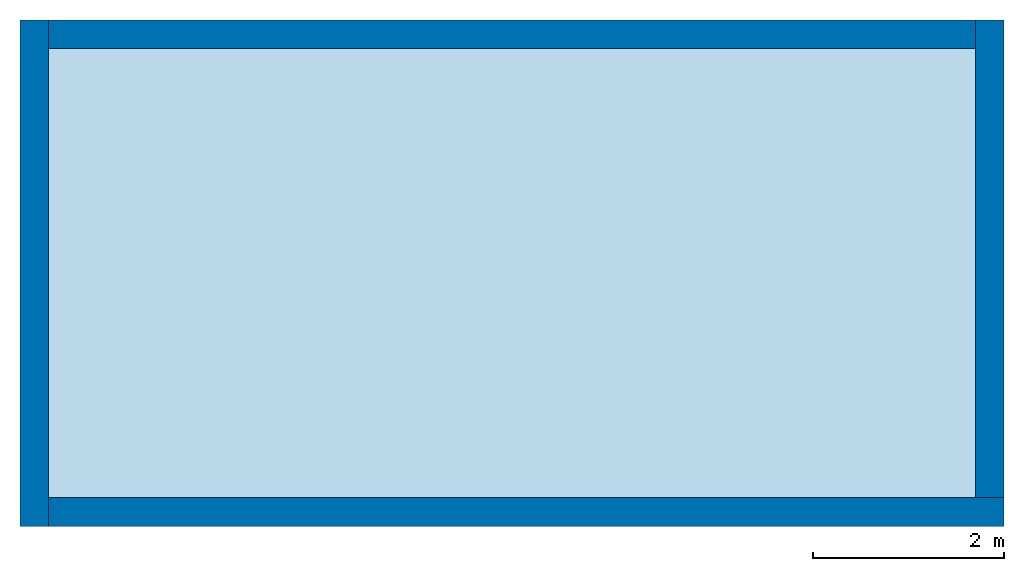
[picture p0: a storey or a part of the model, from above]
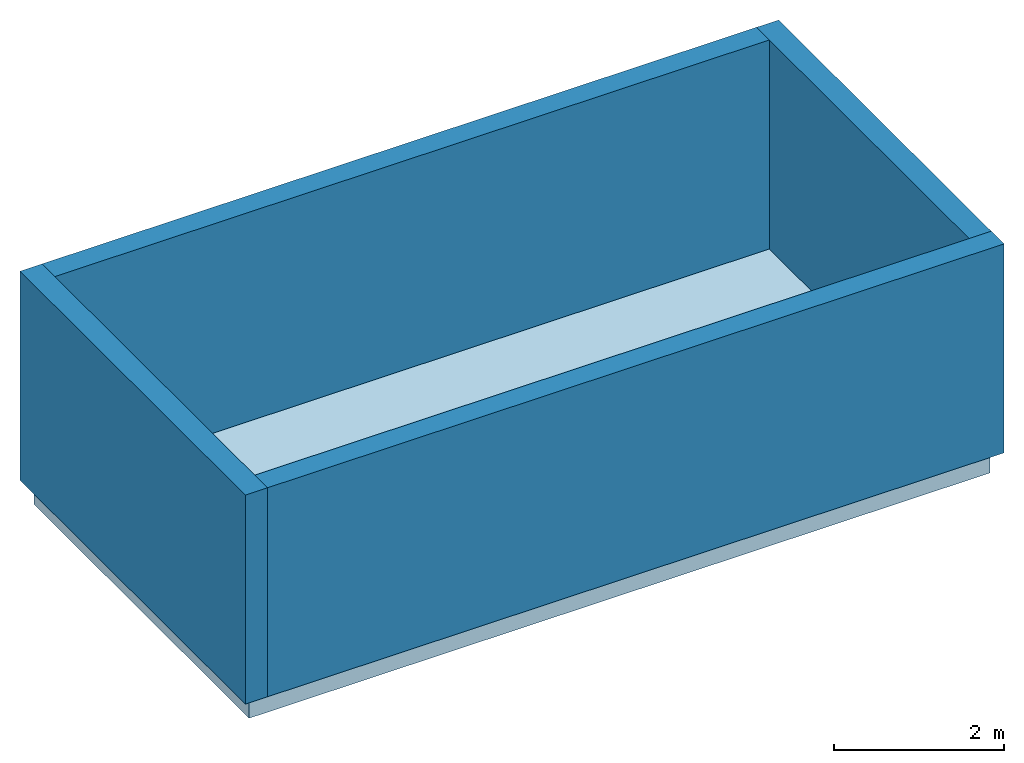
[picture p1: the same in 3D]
Properties of the parts of a building model (IFC2X3)

# File
Description: ViewDefinition [CoordinationView]
File name: Project Number
Time: 2013-12-02T13:34:01
Written by: The EXPRESS Data Manager Version 5.01.0100.02.64mod : 6 Jun 2012
Made in: 20130722_2115(x64) - Exporter 2014.0.2013.0722 - Default UI
Comment: STEP Physical File produced by: The EXPRESS Data Manager Version 5.01.0100.02.64mod : 6 Jun 2012 * Module: EDMstepFileFactory/EDMstandAlone * Creation date: Mon Dec 02 13:34:01 2013 * Host: c10200215 * Database: C:\Users\xphy3\AppData\Local\Temp\{CFBB005A-4551-42A4-96F8-3034134D080C}\ifc * Database version: 5507 * Database creation date: Mon Dec 02 13:33:56 2013 * Schema: IFC2X3 * Model: DataRepository.ifc * Model creation date: Mon Dec 02 13:33:57 2013 * Header model: DataRepository.ifc_HeaderModel * Header model creation date: Mon Dec 02 13:33:57 2013 * EDMuser: sdai-user * EDMgroup: sdai-group * License ID and type: 5605 : Permanent license. Expiry date: * EDMstepFileFactory options: 020000

# IfcProject, Project Number
LongName: Project Name; Phase: Project Status

# IfcSite, Surface:219900
RefLatitude: 51, 30, 0, 549316; RefLongitude: 0, -7, -34, -450321; RefElevation: 0 mm
Phasing - Phase Created: New Construction
Dimensions - Projected Area: 89.79 m2; Surface Area: 89.79 m2

# IfcBuilding
Pset_BuildingCommon - NumberOfStoreys: 1
Other - Project Status: Project Status; Client Name: Owner; Project Issue Date: Issue Date; Project Number: Project Number; Project Address: Enter address here; Project Name: Project Name

# IfcBuildingStorey, Level 0
LongName: Level 0; Elevation: 0 mm
Dimensions - Computation Height: 0 mm
Identity Data - Building Story: yes; Name: Level 0; Structural: no
Constraints - Elevation: 0 mm; Elevation Base: Project Base Point
Graphics - Symbol at End 2 Default: no; Color: 0; Line Pattern: Centre; Line Weight: 1; Symbol: Level Head - Circle: Level Head - Circle; Symbol at End 1 Default: yes

# IfcSlab: Floor:Beam and Block 225mm Susp Ground, Floor:Beam and Block 225mm Susp Ground:217429
In: Level 0
PredefinedType: FLOOR; Material: Concrete, Sand/Cement Screed 65 mm, Rigid insulation 80 mm, Concrete Masonry, Floor Block 100 mm, Concrete, Precast 75 mm
Phasing - Phase Created: New Construction
Dimensions - Volume: 16.265 m3; Perimeter: 30220 mm; Area: 50.828 m2; Thickness: 320 mm
Constraints - Level: Level: Level 0; Room Bounding: yes; Height Offset From Level: 0 mm; Related to Mass: no
Structural - Structural: no; Enable Analytical Model: no
Pset_SlabCommon - Reference: Beam and Block 225mm Susp Ground; IsExternal: no; LoadBearing: yes; ThermalTransmittance: 0.397589 kg/K/s3; PitchAngle: 0 deg
Identity Data - Keynote: E60/130
Construction - Function: Interior; Default Thickness: 320 mm
Analytical Properties - Roughness: 3; Absorptance: 0.7; Heat Transfer Coefficient (U): 0.397589; Thermal mass: 365369; Thermal Resistance (R): 2.51516
Materials and Finishes - Structural Material: Concrete Masonry, Floor Block
Graphics - Coarse Scale Fill Pattern: Solid fill; Coarse Scale Fill Color: 0

# IfcWallStandardCase: Basic Wall:Cav - 102 75i 100 p - Lwt (4)
In: Level 0
Type - PredefinedType: STANDARD; Material: Brick, Common 102.5 mm, Fiberglass Batt 75 mm, Concrete Masonry Units 110 mm, Gypsum Wall Board 12.5 mm
Type - Identity Data - Keynote: F10
Type - Construction - Wrapping at Inserts: Both; Function: Exterior; Width: 300 mm
Type - Materials and Finishes - Structural Material: Concrete Masonry Units
Type - Graphics - Coarse Scale Fill Pattern: Solid fill; Coarse Scale Fill Color: 12632256
Type - Analytical Properties - Absorptance: 0.7; Roughness: 3; Heat Transfer Coefficient (U): 0.235792; Thermal mass: 313533; Thermal Resistance (R): 4.24103
Constraints - Base is Attached: no; Related to Mass: no; Base Constraint: Level: Level 0; Top is Attached: no; Base Extension Distance: 0 mm; Base Offset: 0 mm; Top Offset: 0 mm; Top Extension Distance: 0 mm; Location Line: Wall Centerline; Unconnected Height: 3000 mm; Top Constraint: Level: Level 1; Room Bounding: yes
Structural - Enable Analytical Model: no; Structural: no; Structural Usage: Non-bearing
Phasing - Phase Created: New Construction
Pset_WallCommon - Reference: Cav - 102 75i 100 p - Lwt; LoadBearing: no; ExtendToStructure: no; IsExternal: yes; ThermalTransmittance: 0.235792 kg/K/s3
Name (Basic Wall:Cav - 102 75i 100 p - Lwt:...) | Area (m2) | Volume (m3) | Length (mm)
217140 | 15.9 | 4.77 | 5000
217231 | 30 | 9 | 10000
217273 | 15 | 4.5 | 5000
217327 | 29.1 | 8.73 | 10000
